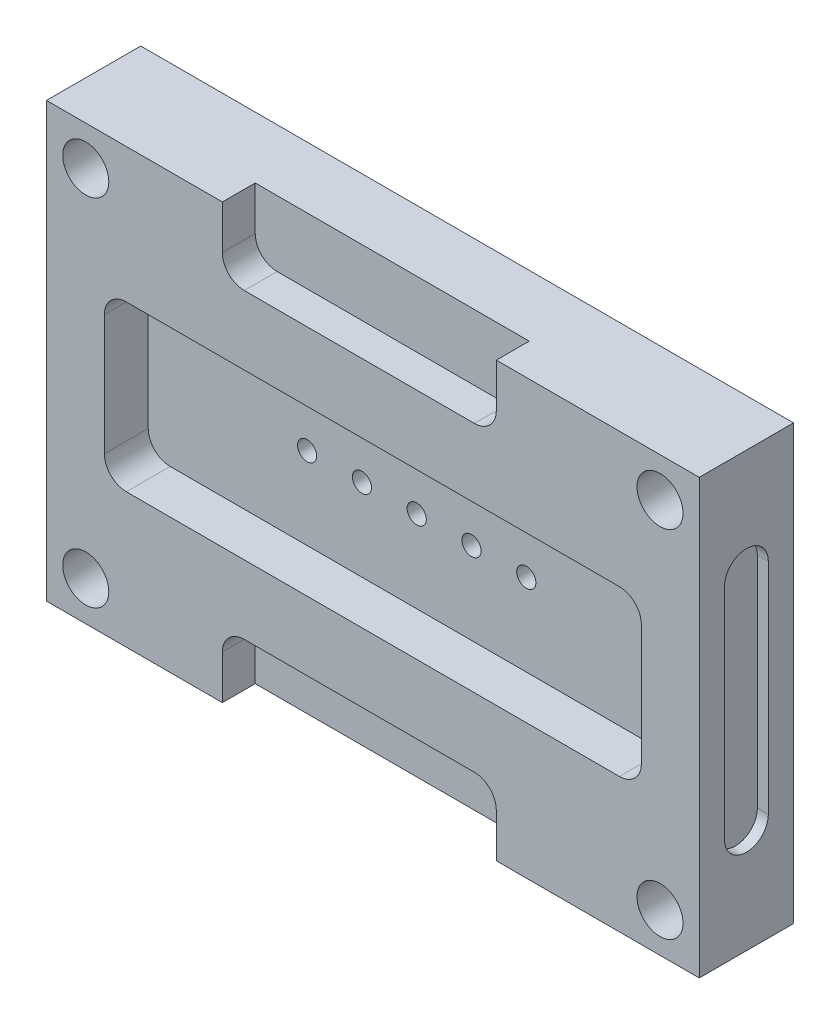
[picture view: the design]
ISO-10303-21;
HEADER;
FILE_DESCRIPTION(('STEP AP214'),'2;1');
FILE_NAME('part.step','',(''),(''),'','','');
FILE_SCHEMA(('AUTOMOTIVE_DESIGN { 1 0 10303 214 1 1 1 1 }'));
ENDSEC;
DATA;
#1=APPLICATION_CONTEXT('core data for automotive mechanical design processes');
#2=APPLICATION_PROTOCOL_DEFINITION('international standard','automotive_design',2000,#1);
#3=PRODUCT_CONTEXT('',#1,'mechanical');
#4=PRODUCT('Part','Part','',(#3));
#5=PRODUCT_RELATED_PRODUCT_CATEGORY('part','',(#4));
#6=PRODUCT_DEFINITION_FORMATION('','',#4);
#7=PRODUCT_DEFINITION_CONTEXT('part definition',#1,'design');
#8=PRODUCT_DEFINITION('design','',#6,#7);
#9=PRODUCT_DEFINITION_SHAPE('','',#8);
#10=(LENGTH_UNIT() NAMED_UNIT(*) SI_UNIT(.MILLI.,.METRE.));
#11=(NAMED_UNIT(*) PLANE_ANGLE_UNIT() SI_UNIT($,.RADIAN.));
#12=(NAMED_UNIT(*) SI_UNIT($,.STERADIAN.) SOLID_ANGLE_UNIT());
#13=UNCERTAINTY_MEASURE_WITH_UNIT(LENGTH_MEASURE(1.E-05),#10,'distance_accuracy_value','');
#14=(GEOMETRIC_REPRESENTATION_CONTEXT(3) GLOBAL_UNCERTAINTY_ASSIGNED_CONTEXT((#13)) GLOBAL_UNIT_ASSIGNED_CONTEXT((#10,
#11,#12)) REPRESENTATION_CONTEXT('',''));
#15=CARTESIAN_POINT('',(0.,0.,0.));
#16=DIRECTION('',(0.,0.,1.));
#17=DIRECTION('',(1.,0.,0.));
#18=AXIS2_PLACEMENT_3D('',#15,#16,#17);
#19=CARTESIAN_POINT('',(-297.85,197.85,86.));
#20=DIRECTION('',(1.,0.,0.));
#21=DIRECTION('',(0.,0.,-1.));
#22=AXIS2_PLACEMENT_3D('',#19,#20,#21);
#23=PLANE('',#22);
#24=DIRECTION('',(0.,-1.,0.));
#25=VECTOR('',#24,1.);
#26=CARTESIAN_POINT('',(-297.85,197.85,0.));
#27=LINE('',#26,#25);
#28=CARTESIAN_POINT('',(-297.85,197.85,0.));
#29=VERTEX_POINT('',#28);
#30=CARTESIAN_POINT('',(-297.85,-197.85,0.));
#31=VERTEX_POINT('',#30);
#32=EDGE_CURVE('E426',#29,#31,#27,.T.);
#33=ORIENTED_EDGE('',*,*,#32,.T.);
#34=DIRECTION('',(0.,0.,-1.));
#35=VECTOR('',#34,1.);
#36=CARTESIAN_POINT('',(-297.85,-197.85,86.));
#37=LINE('',#36,#35);
#38=CARTESIAN_POINT('',(-297.85,-197.85,86.));
#39=VERTEX_POINT('',#38);
#40=EDGE_CURVE('E12',#39,#31,#37,.T.);
#41=ORIENTED_EDGE('',*,*,#40,.F.);
#42=DIRECTION('',(0.,-1.,0.));
#43=VECTOR('',#42,1.);
#44=CARTESIAN_POINT('',(-297.85,197.85,86.));
#45=LINE('',#44,#43);
#46=CARTESIAN_POINT('',(-297.85,197.85,86.));
#47=VERTEX_POINT('',#46);
#48=EDGE_CURVE('E443',#47,#39,#45,.T.);
#49=ORIENTED_EDGE('',*,*,#48,.F.);
#50=DIRECTION('',(0.,0.,-1.));
#51=VECTOR('',#50,1.);
#52=CARTESIAN_POINT('',(-297.85,197.85,86.));
#53=LINE('',#52,#51);
#54=EDGE_CURVE('E292',#47,#29,#53,.T.);
#55=ORIENTED_EDGE('',*,*,#54,.T.);
#56=EDGE_LOOP('',(#33,#41,#49,#55));
#57=FACE_BOUND('',#56,.T.);
#58=ADVANCED_FACE('F41',(#57),#23,.F.);
#59=CARTESIAN_POINT('',(297.85,-197.85,86.));
#60=DIRECTION('',(0.,-1.,0.));
#61=DIRECTION('',(1.,0.,0.));
#62=AXIS2_PLACEMENT_3D('',#59,#60,#61);
#63=PLANE('',#62);
#64=DIRECTION('',(0.,0.,1.));
#65=VECTOR('',#64,1.);
#66=CARTESIAN_POINT('',(112.638390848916,-197.85,56.));
#67=LINE('',#66,#65);
#68=CARTESIAN_POINT('',(112.638390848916,-197.85,56.));
#69=VERTEX_POINT('',#68);
#70=CARTESIAN_POINT('',(112.638390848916,-197.85,86.));
#71=VERTEX_POINT('',#70);
#72=EDGE_CURVE('E776',#69,#71,#67,.T.);
#73=ORIENTED_EDGE('',*,*,#72,.F.);
#74=DIRECTION('',(1.,0.,0.));
#75=VECTOR('',#74,1.);
#76=CARTESIAN_POINT('',(-137.361609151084,-197.85,56.));
#77=LINE('',#76,#75);
#78=CARTESIAN_POINT('',(-137.361609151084,-197.85,56.));
#79=VERTEX_POINT('',#78);
#80=EDGE_CURVE('E542',#79,#69,#77,.T.);
#81=ORIENTED_EDGE('',*,*,#80,.F.);
#82=DIRECTION('',(0.,0.,1.));
#83=VECTOR('',#82,1.);
#84=CARTESIAN_POINT('',(-137.361609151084,-197.85,56.));
#85=LINE('',#84,#83);
#86=CARTESIAN_POINT('',(-137.361609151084,-197.85,86.));
#87=VERTEX_POINT('',#86);
#88=EDGE_CURVE('E765',#79,#87,#85,.T.);
#89=ORIENTED_EDGE('',*,*,#88,.T.);
#90=DIRECTION('',(-1.,0.,0.));
#91=VECTOR('',#90,1.);
#92=CARTESIAN_POINT('',(297.85,-197.85,86.));
#93=LINE('',#92,#91);
#94=EDGE_CURVE('E442',#87,#39,#93,.T.);
#95=ORIENTED_EDGE('',*,*,#94,.T.);
#96=ORIENTED_EDGE('',*,*,#40,.T.);
#97=DIRECTION('',(-1.,0.,0.));
#98=VECTOR('',#97,1.);
#99=CARTESIAN_POINT('',(297.85,-197.85,0.));
#100=LINE('',#99,#98);
#101=CARTESIAN_POINT('',(297.85,-197.85,0.));
#102=VERTEX_POINT('',#101);
#103=EDGE_CURVE('E283',#102,#31,#100,.T.);
#104=ORIENTED_EDGE('',*,*,#103,.F.);
#105=DIRECTION('',(0.,0.,-1.));
#106=VECTOR('',#105,1.);
#107=CARTESIAN_POINT('',(297.85,-197.85,86.));
#108=LINE('',#107,#106);
#109=CARTESIAN_POINT('',(297.85,-197.85,86.));
#110=VERTEX_POINT('',#109);
#111=EDGE_CURVE('E48',#110,#102,#108,.T.);
#112=ORIENTED_EDGE('',*,*,#111,.F.);
#113=EDGE_CURVE('E439',#110,#71,#93,.T.);
#114=ORIENTED_EDGE('',*,*,#113,.T.);
#115=EDGE_LOOP('',(#73,#81,#89,#95,#96,#104,#112,#114));
#116=FACE_BOUND('',#115,.T.);
#117=ADVANCED_FACE('F742',(#116),#63,.T.);
#118=CARTESIAN_POINT('',(297.85,-197.85,86.));
#119=DIRECTION('',(-1.,0.,0.));
#120=DIRECTION('',(0.,-1.,0.));
#121=AXIS2_PLACEMENT_3D('',#118,#119,#120);
#122=PLANE('',#121);
#123=DIRECTION('',(0.,1.,0.));
#124=VECTOR('',#123,1.);
#125=CARTESIAN_POINT('',(297.85,-100.,23.));
#126=LINE('',#125,#124);
#127=CARTESIAN_POINT('',(297.85,-100.,23.));
#128=VERTEX_POINT('',#127);
#129=CARTESIAN_POINT('',(297.85,100.,23.));
#130=VERTEX_POINT('',#129);
#131=EDGE_CURVE('E552',#128,#130,#126,.T.);
#132=ORIENTED_EDGE('',*,*,#131,.F.);
#133=CARTESIAN_POINT('',(297.85,-100.,43.));
#134=DIRECTION('',(1.,0.,0.));
#135=DIRECTION('',(0.,1.,0.));
#136=AXIS2_PLACEMENT_3D('',#133,#134,#135);
#137=CIRCLE('',#136,20.);
#138=CARTESIAN_POINT('',(297.85,-100.,63.));
#139=VERTEX_POINT('',#138);
#140=EDGE_CURVE('E55',#139,#128,#137,.T.);
#141=ORIENTED_EDGE('',*,*,#140,.F.);
#142=DIRECTION('',(0.,-1.,0.));
#143=VECTOR('',#142,1.);
#144=CARTESIAN_POINT('',(297.85,-100.,63.));
#145=LINE('',#144,#143);
#146=CARTESIAN_POINT('',(297.85,100.,63.));
#147=VERTEX_POINT('',#146);
#148=EDGE_CURVE('E244',#147,#139,#145,.T.);
#149=ORIENTED_EDGE('',*,*,#148,.F.);
#150=CARTESIAN_POINT('',(297.85,100.,43.));
#151=DIRECTION('',(1.,0.,0.));
#152=DIRECTION('',(0.,1.,0.));
#153=AXIS2_PLACEMENT_3D('',#150,#151,#152);
#154=CIRCLE('',#153,20.);
#155=EDGE_CURVE('E247',#130,#147,#154,.T.);
#156=ORIENTED_EDGE('',*,*,#155,.F.);
#157=EDGE_LOOP('',(#132,#141,#149,#156));
#158=FACE_BOUND('',#157,.T.);
#159=DIRECTION('',(0.,1.,0.));
#160=VECTOR('',#159,1.);
#161=CARTESIAN_POINT('',(297.85,-197.85,0.));
#162=LINE('',#161,#160);
#163=CARTESIAN_POINT('',(297.85,197.85,0.));
#164=VERTEX_POINT('',#163);
#165=EDGE_CURVE('E277',#102,#164,#162,.T.);
#166=ORIENTED_EDGE('',*,*,#165,.T.);
#167=DIRECTION('',(0.,0.,-1.));
#168=VECTOR('',#167,1.);
#169=CARTESIAN_POINT('',(297.85,197.85,86.));
#170=LINE('',#169,#168);
#171=CARTESIAN_POINT('',(297.85,197.85,86.));
#172=VERTEX_POINT('',#171);
#173=EDGE_CURVE('E290',#172,#164,#170,.T.);
#174=ORIENTED_EDGE('',*,*,#173,.F.);
#175=DIRECTION('',(0.,1.,0.));
#176=VECTOR('',#175,1.);
#177=CARTESIAN_POINT('',(297.85,-197.85,86.));
#178=LINE('',#177,#176);
#179=EDGE_CURVE('E423',#110,#172,#178,.T.);
#180=ORIENTED_EDGE('',*,*,#179,.F.);
#181=ORIENTED_EDGE('',*,*,#111,.T.);
#182=EDGE_LOOP('',(#166,#174,#180,#181));
#183=FACE_BOUND('',#182,.T.);
#184=ADVANCED_FACE('F568',(#158,#183),#122,.F.);
#185=CARTESIAN_POINT('',(-297.85,197.85,86.));
#186=DIRECTION('',(0.,1.,0.));
#187=DIRECTION('',(0.,0.,1.));
#188=AXIS2_PLACEMENT_3D('',#185,#186,#187);
#189=PLANE('',#188);
#190=DIRECTION('',(0.,0.,1.));
#191=VECTOR('',#190,1.);
#192=CARTESIAN_POINT('',(-137.361609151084,197.85,56.));
#193=LINE('',#192,#191);
#194=CARTESIAN_POINT('',(-137.361609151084,197.85,56.));
#195=VERTEX_POINT('',#194);
#196=CARTESIAN_POINT('',(-137.361609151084,197.85,86.));
#197=VERTEX_POINT('',#196);
#198=EDGE_CURVE('E349',#195,#197,#193,.T.);
#199=ORIENTED_EDGE('',*,*,#198,.F.);
#200=DIRECTION('',(-1.,0.,0.));
#201=VECTOR('',#200,1.);
#202=CARTESIAN_POINT('',(-137.361609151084,197.85,56.));
#203=LINE('',#202,#201);
#204=CARTESIAN_POINT('',(112.638390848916,197.85,56.));
#205=VERTEX_POINT('',#204);
#206=EDGE_CURVE('E341',#205,#195,#203,.T.);
#207=ORIENTED_EDGE('',*,*,#206,.F.);
#208=DIRECTION('',(0.,0.,1.));
#209=VECTOR('',#208,1.);
#210=CARTESIAN_POINT('',(112.638390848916,197.85,56.));
#211=LINE('',#210,#209);
#212=CARTESIAN_POINT('',(112.638390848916,197.85,86.));
#213=VERTEX_POINT('',#212);
#214=EDGE_CURVE('E353',#205,#213,#211,.T.);
#215=ORIENTED_EDGE('',*,*,#214,.T.);
#216=DIRECTION('',(1.,0.,0.));
#217=VECTOR('',#216,1.);
#218=CARTESIAN_POINT('',(-297.85,197.85,86.));
#219=LINE('',#218,#217);
#220=EDGE_CURVE('E422',#213,#172,#219,.T.);
#221=ORIENTED_EDGE('',*,*,#220,.T.);
#222=ORIENTED_EDGE('',*,*,#173,.T.);
#223=DIRECTION('',(1.,0.,0.));
#224=VECTOR('',#223,1.);
#225=CARTESIAN_POINT('',(-297.85,197.85,0.));
#226=LINE('',#225,#224);
#227=EDGE_CURVE('E282',#29,#164,#226,.T.);
#228=ORIENTED_EDGE('',*,*,#227,.F.);
#229=ORIENTED_EDGE('',*,*,#54,.F.);
#230=EDGE_CURVE('E418',#47,#197,#219,.T.);
#231=ORIENTED_EDGE('',*,*,#230,.T.);
#232=EDGE_LOOP('',(#199,#207,#215,#221,#222,#228,#229,#231));
#233=FACE_BOUND('',#232,.T.);
#234=ADVANCED_FACE('F770',(#233),#189,.T.);
#235=CARTESIAN_POINT('',(-297.85,197.85,86.));
#236=DIRECTION('',(0.,0.,1.));
#237=DIRECTION('',(1.,0.,0.));
#238=AXIS2_PLACEMENT_3D('',#235,#236,#237);
#239=PLANE('',#238);
#240=DIRECTION('',(0.,1.,0.));
#241=VECTOR('',#240,1.);
#242=CARTESIAN_POINT('',(112.638390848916,-197.85,86.));
#243=LINE('',#242,#241);
#244=CARTESIAN_POINT('',(112.638390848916,-157.85,86.));
#245=VERTEX_POINT('',#244);
#246=EDGE_CURVE('E459',#71,#245,#243,.T.);
#247=ORIENTED_EDGE('',*,*,#246,.F.);
#248=ORIENTED_EDGE('',*,*,#113,.F.);
#249=ORIENTED_EDGE('',*,*,#179,.T.);
#250=ORIENTED_EDGE('',*,*,#220,.F.);
#251=DIRECTION('',(0.,1.,0.));
#252=VECTOR('',#251,1.);
#253=CARTESIAN_POINT('',(112.638390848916,197.85,86.));
#254=LINE('',#253,#252);
#255=CARTESIAN_POINT('',(112.638390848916,157.85,86.));
#256=VERTEX_POINT('',#255);
#257=EDGE_CURVE('E354',#256,#213,#254,.T.);
#258=ORIENTED_EDGE('',*,*,#257,.F.);
#259=CARTESIAN_POINT('',(92.6383908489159,157.85,86.));
#260=DIRECTION('',(0.,0.,1.));
#261=DIRECTION('',(-1.,0.,0.));
#262=AXIS2_PLACEMENT_3D('',#259,#260,#261);
#263=CIRCLE('',#262,20.);
#264=CARTESIAN_POINT('',(92.6383908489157,137.85,86.));
#265=VERTEX_POINT('',#264);
#266=EDGE_CURVE('E389',#265,#256,#263,.T.);
#267=ORIENTED_EDGE('',*,*,#266,.F.);
#268=DIRECTION('',(1.,0.,0.));
#269=VECTOR('',#268,1.);
#270=CARTESIAN_POINT('',(92.6383908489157,137.85,86.));
#271=LINE('',#270,#269);
#272=CARTESIAN_POINT('',(-117.361609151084,137.85,86.));
#273=VERTEX_POINT('',#272);
#274=EDGE_CURVE('E371',#273,#265,#271,.T.);
#275=ORIENTED_EDGE('',*,*,#274,.F.);
#276=CARTESIAN_POINT('',(-117.361609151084,157.85,86.));
#277=DIRECTION('',(0.,0.,1.));
#278=DIRECTION('',(-1.,0.,0.));
#279=AXIS2_PLACEMENT_3D('',#276,#277,#278);
#280=CIRCLE('',#279,20.);
#281=CARTESIAN_POINT('',(-137.361609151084,157.85,86.));
#282=VERTEX_POINT('',#281);
#283=EDGE_CURVE('E379',#282,#273,#280,.T.);
#284=ORIENTED_EDGE('',*,*,#283,.F.);
#285=DIRECTION('',(0.,-1.,0.));
#286=VECTOR('',#285,1.);
#287=CARTESIAN_POINT('',(-137.361609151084,197.85,86.));
#288=LINE('',#287,#286);
#289=EDGE_CURVE('E383',#197,#282,#288,.T.);
#290=ORIENTED_EDGE('',*,*,#289,.F.);
#291=ORIENTED_EDGE('',*,*,#230,.F.);
#292=ORIENTED_EDGE('',*,*,#48,.T.);
#293=ORIENTED_EDGE('',*,*,#94,.F.);
#294=DIRECTION('',(0.,-1.,0.));
#295=VECTOR('',#294,1.);
#296=CARTESIAN_POINT('',(-137.361609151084,-197.85,86.));
#297=LINE('',#296,#295);
#298=CARTESIAN_POINT('',(-137.361609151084,-157.85,86.));
#299=VERTEX_POINT('',#298);
#300=EDGE_CURVE('E457',#299,#87,#297,.T.);
#301=ORIENTED_EDGE('',*,*,#300,.F.);
#302=CARTESIAN_POINT('',(-117.361609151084,-157.85,86.));
#303=DIRECTION('',(0.,0.,1.));
#304=DIRECTION('',(1.,0.,0.));
#305=AXIS2_PLACEMENT_3D('',#302,#303,#304);
#306=CIRCLE('',#305,20.);
#307=CARTESIAN_POINT('',(-117.361609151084,-137.85,86.));
#308=VERTEX_POINT('',#307);
#309=EDGE_CURVE('E460',#308,#299,#306,.T.);
#310=ORIENTED_EDGE('',*,*,#309,.F.);
#311=DIRECTION('',(-1.,0.,0.));
#312=VECTOR('',#311,1.);
#313=CARTESIAN_POINT('',(92.6383908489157,-137.85,86.));
#314=LINE('',#313,#312);
#315=CARTESIAN_POINT('',(92.6383908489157,-137.85,86.));
#316=VERTEX_POINT('',#315);
#317=EDGE_CURVE('E472',#316,#308,#314,.T.);
#318=ORIENTED_EDGE('',*,*,#317,.F.);
#319=CARTESIAN_POINT('',(92.6383908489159,-157.85,86.));
#320=DIRECTION('',(0.,0.,1.));
#321=DIRECTION('',(1.,0.,0.));
#322=AXIS2_PLACEMENT_3D('',#319,#320,#321);
#323=CIRCLE('',#322,20.);
#324=EDGE_CURVE('E63',#245,#316,#323,.T.);
#325=ORIENTED_EDGE('',*,*,#324,.F.);
#326=EDGE_LOOP('',(#247,#248,#249,#250,#258,#267,#275,#284,#290,#291,#292,#293,#301,#310,#318,#325));
#327=FACE_BOUND('',#326,.T.);
#328=CARTESIAN_POINT('',(-225.,55.,86.));
#329=DIRECTION('',(0.,0.,1.));
#330=DIRECTION('',(-1.,0.,0.));
#331=AXIS2_PLACEMENT_3D('',#328,#329,#330);
#332=CIRCLE('',#331,20.);
#333=CARTESIAN_POINT('',(-225.,75.,86.));
#334=VERTEX_POINT('',#333);
#335=CARTESIAN_POINT('',(-245.,55.,86.));
#336=VERTEX_POINT('',#335);
#337=EDGE_CURVE('E307',#334,#336,#332,.T.);
#338=ORIENTED_EDGE('',*,*,#337,.F.);
#339=DIRECTION('',(-1.,0.,0.));
#340=VECTOR('',#339,1.);
#341=CARTESIAN_POINT('',(-225.,75.,86.));
#342=LINE('',#341,#340);
#343=CARTESIAN_POINT('',(225.,75.,86.));
#344=VERTEX_POINT('',#343);
#345=EDGE_CURVE('E689',#344,#334,#342,.T.);
#346=ORIENTED_EDGE('',*,*,#345,.F.);
#347=CARTESIAN_POINT('',(225.,55.,86.));
#348=DIRECTION('',(0.,0.,1.));
#349=DIRECTION('',(-1.,0.,0.));
#350=AXIS2_PLACEMENT_3D('',#347,#348,#349);
#351=CIRCLE('',#350,20.);
#352=CARTESIAN_POINT('',(245.,55.,86.));
#353=VERTEX_POINT('',#352);
#354=EDGE_CURVE('E695',#353,#344,#351,.T.);
#355=ORIENTED_EDGE('',*,*,#354,.F.);
#356=DIRECTION('',(0.,1.,0.));
#357=VECTOR('',#356,1.);
#358=CARTESIAN_POINT('',(245.,-55.,86.));
#359=LINE('',#358,#357);
#360=CARTESIAN_POINT('',(245.,-55.,86.));
#361=VERTEX_POINT('',#360);
#362=EDGE_CURVE('E697',#361,#353,#359,.T.);
#363=ORIENTED_EDGE('',*,*,#362,.F.);
#364=CARTESIAN_POINT('',(225.,-55.,86.));
#365=DIRECTION('',(0.,0.,1.));
#366=DIRECTION('',(1.,0.,0.));
#367=AXIS2_PLACEMENT_3D('',#364,#365,#366);
#368=CIRCLE('',#367,20.);
#369=CARTESIAN_POINT('',(225.,-75.,86.));
#370=VERTEX_POINT('',#369);
#371=EDGE_CURVE('E725',#370,#361,#368,.T.);
#372=ORIENTED_EDGE('',*,*,#371,.F.);
#373=DIRECTION('',(1.,0.,0.));
#374=VECTOR('',#373,1.);
#375=CARTESIAN_POINT('',(-225.,-75.,86.));
#376=LINE('',#375,#374);
#377=CARTESIAN_POINT('',(-225.,-75.,86.));
#378=VERTEX_POINT('',#377);
#379=EDGE_CURVE('E715',#378,#370,#376,.T.);
#380=ORIENTED_EDGE('',*,*,#379,.F.);
#381=CARTESIAN_POINT('',(-225.,-55.,86.));
#382=DIRECTION('',(0.,0.,1.));
#383=DIRECTION('',(-1.,0.,0.));
#384=AXIS2_PLACEMENT_3D('',#381,#382,#383);
#385=CIRCLE('',#384,20.);
#386=CARTESIAN_POINT('',(-245.,-55.,86.));
#387=VERTEX_POINT('',#386);
#388=EDGE_CURVE('E306',#387,#378,#385,.T.);
#389=ORIENTED_EDGE('',*,*,#388,.F.);
#390=DIRECTION('',(0.,-1.,0.));
#391=VECTOR('',#390,1.);
#392=CARTESIAN_POINT('',(-245.,-55.,86.));
#393=LINE('',#392,#391);
#394=EDGE_CURVE('E301',#336,#387,#393,.T.);
#395=ORIENTED_EDGE('',*,*,#394,.F.);
#396=EDGE_LOOP('',(#338,#346,#355,#363,#372,#380,#389,#395));
#397=FACE_BOUND('',#396,.T.);
#398=CARTESIAN_POINT('',(262.,162.,85.99999999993));
#399=DIRECTION('',(0.,0.,1.));
#400=DIRECTION('',(1.,0.,0.));
#401=AXIS2_PLACEMENT_3D('',#398,#399,#400);
#402=CIRCLE('',#401,21.);
#403=CARTESIAN_POINT('',(283.,162.,85.99999999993));
#404=VERTEX_POINT('',#403);
#405=EDGE_CURVE('E615',#404,#404,#402,.T.);
#406=ORIENTED_EDGE('',*,*,#405,.F.);
#407=EDGE_LOOP('',(#406));
#408=FACE_BOUND('',#407,.T.);
#409=CARTESIAN_POINT('',(-262.,162.,85.9999999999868));
#410=DIRECTION('',(0.,0.,1.));
#411=DIRECTION('',(1.,0.,0.));
#412=AXIS2_PLACEMENT_3D('',#409,#410,#411);
#413=CIRCLE('',#412,21.);
#414=CARTESIAN_POINT('',(-241.,162.,85.9999999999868));
#415=VERTEX_POINT('',#414);
#416=EDGE_CURVE('E602',#415,#415,#413,.T.);
#417=ORIENTED_EDGE('',*,*,#416,.F.);
#418=EDGE_LOOP('',(#417));
#419=FACE_BOUND('',#418,.T.);
#420=CARTESIAN_POINT('',(-262.,-162.,85.9999999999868));
#421=DIRECTION('',(0.,0.,1.));
#422=DIRECTION('',(1.,0.,0.));
#423=AXIS2_PLACEMENT_3D('',#420,#421,#422);
#424=CIRCLE('',#423,21.);
#425=CARTESIAN_POINT('',(-241.,-162.,85.9999999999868));
#426=VERTEX_POINT('',#425);
#427=EDGE_CURVE('E601',#426,#426,#424,.T.);
#428=ORIENTED_EDGE('',*,*,#427,.F.);
#429=EDGE_LOOP('',(#428));
#430=FACE_BOUND('',#429,.T.);
#431=CARTESIAN_POINT('',(262.,-162.,86.));
#432=DIRECTION('',(0.,0.,1.));
#433=DIRECTION('',(1.,0.,0.));
#434=AXIS2_PLACEMENT_3D('',#431,#432,#433);
#435=CIRCLE('',#434,21.);
#436=CARTESIAN_POINT('',(283.,-162.,86.));
#437=VERTEX_POINT('',#436);
#438=EDGE_CURVE('E600',#437,#437,#435,.T.);
#439=ORIENTED_EDGE('',*,*,#438,.F.);
#440=EDGE_LOOP('',(#439));
#441=FACE_BOUND('',#440,.T.);
#442=ADVANCED_FACE('F386',(#327,#397,#408,#419,#430,#441),#239,.T.);
#443=CARTESIAN_POINT('',(-297.85,197.85,0.));
#444=DIRECTION('',(0.,0.,1.));
#445=DIRECTION('',(1.,0.,0.));
#446=AXIS2_PLACEMENT_3D('',#443,#444,#445);
#447=PLANE('',#446);
#448=CARTESIAN_POINT('',(0.,0.,0.));
#449=DIRECTION('',(0.,0.,1.));
#450=DIRECTION('',(1.,0.,0.));
#451=AXIS2_PLACEMENT_3D('',#448,#449,#450);
#452=CIRCLE('',#451,8.74999999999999);
#453=CARTESIAN_POINT('',(8.74999999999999,0.,0.));
#454=VERTEX_POINT('',#453);
#455=EDGE_CURVE('E817',#454,#454,#452,.T.);
#456=ORIENTED_EDGE('',*,*,#455,.T.);
#457=EDGE_LOOP('',(#456));
#458=FACE_BOUND('',#457,.T.);
#459=CARTESIAN_POINT('',(-50.,0.,0.));
#460=DIRECTION('',(0.,0.,1.));
#461=DIRECTION('',(1.,0.,0.));
#462=AXIS2_PLACEMENT_3D('',#459,#460,#461);
#463=CIRCLE('',#462,8.74999999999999);
#464=CARTESIAN_POINT('',(-41.25,0.,0.));
#465=VERTEX_POINT('',#464);
#466=EDGE_CURVE('E805',#465,#465,#463,.T.);
#467=ORIENTED_EDGE('',*,*,#466,.T.);
#468=EDGE_LOOP('',(#467));
#469=FACE_BOUND('',#468,.T.);
#470=CARTESIAN_POINT('',(-100.,0.,0.));
#471=DIRECTION('',(0.,0.,1.));
#472=DIRECTION('',(1.,0.,0.));
#473=AXIS2_PLACEMENT_3D('',#470,#471,#472);
#474=CIRCLE('',#473,8.74999999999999);
#475=CARTESIAN_POINT('',(-91.25,0.,0.));
#476=VERTEX_POINT('',#475);
#477=EDGE_CURVE('E791',#476,#476,#474,.T.);
#478=ORIENTED_EDGE('',*,*,#477,.T.);
#479=EDGE_LOOP('',(#478));
#480=FACE_BOUND('',#479,.T.);
#481=CARTESIAN_POINT('',(50.,0.,0.));
#482=DIRECTION('',(0.,0.,1.));
#483=DIRECTION('',(1.,0.,0.));
#484=AXIS2_PLACEMENT_3D('',#481,#482,#483);
#485=CIRCLE('',#484,8.74999999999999);
#486=CARTESIAN_POINT('',(58.75,0.,0.));
#487=VERTEX_POINT('',#486);
#488=EDGE_CURVE('E575',#487,#487,#485,.T.);
#489=ORIENTED_EDGE('',*,*,#488,.T.);
#490=EDGE_LOOP('',(#489));
#491=FACE_BOUND('',#490,.T.);
#492=CARTESIAN_POINT('',(100.,0.,0.));
#493=DIRECTION('',(0.,0.,1.));
#494=DIRECTION('',(1.,0.,0.));
#495=AXIS2_PLACEMENT_3D('',#492,#493,#494);
#496=CIRCLE('',#495,8.74999999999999);
#497=CARTESIAN_POINT('',(108.75,0.,0.));
#498=VERTEX_POINT('',#497);
#499=EDGE_CURVE('E251',#498,#498,#496,.T.);
#500=ORIENTED_EDGE('',*,*,#499,.T.);
#501=EDGE_LOOP('',(#500));
#502=FACE_BOUND('',#501,.T.);
#503=CARTESIAN_POINT('',(262.,162.,0.));
#504=DIRECTION('',(0.,0.,1.));
#505=DIRECTION('',(1.,0.,0.));
#506=AXIS2_PLACEMENT_3D('',#503,#504,#505);
#507=CIRCLE('',#506,21.);
#508=CARTESIAN_POINT('',(283.,162.,0.));
#509=VERTEX_POINT('',#508);
#510=EDGE_CURVE('E326',#509,#509,#507,.T.);
#511=ORIENTED_EDGE('',*,*,#510,.T.);
#512=EDGE_LOOP('',(#511));
#513=FACE_BOUND('',#512,.T.);
#514=CARTESIAN_POINT('',(-262.,162.,0.));
#515=DIRECTION('',(0.,0.,1.));
#516=DIRECTION('',(1.,0.,0.));
#517=AXIS2_PLACEMENT_3D('',#514,#515,#516);
#518=CIRCLE('',#517,21.);
#519=CARTESIAN_POINT('',(-241.,162.,0.));
#520=VERTEX_POINT('',#519);
#521=EDGE_CURVE('E612',#520,#520,#518,.T.);
#522=ORIENTED_EDGE('',*,*,#521,.T.);
#523=EDGE_LOOP('',(#522));
#524=FACE_BOUND('',#523,.T.);
#525=CARTESIAN_POINT('',(-262.,-162.,0.));
#526=DIRECTION('',(0.,0.,1.));
#527=DIRECTION('',(1.,0.,0.));
#528=AXIS2_PLACEMENT_3D('',#525,#526,#527);
#529=CIRCLE('',#528,21.);
#530=CARTESIAN_POINT('',(-241.,-162.,0.));
#531=VERTEX_POINT('',#530);
#532=EDGE_CURVE('E596',#531,#531,#529,.T.);
#533=ORIENTED_EDGE('',*,*,#532,.T.);
#534=EDGE_LOOP('',(#533));
#535=FACE_BOUND('',#534,.T.);
#536=CARTESIAN_POINT('',(262.,-162.,0.));
#537=DIRECTION('',(0.,0.,1.));
#538=DIRECTION('',(1.,0.,0.));
#539=AXIS2_PLACEMENT_3D('',#536,#537,#538);
#540=CIRCLE('',#539,21.);
#541=CARTESIAN_POINT('',(283.,-162.,0.));
#542=VERTEX_POINT('',#541);
#543=EDGE_CURVE('E622',#542,#542,#540,.T.);
#544=ORIENTED_EDGE('',*,*,#543,.T.);
#545=EDGE_LOOP('',(#544));
#546=FACE_BOUND('',#545,.T.);
#547=ORIENTED_EDGE('',*,*,#32,.F.);
#548=ORIENTED_EDGE('',*,*,#227,.T.);
#549=ORIENTED_EDGE('',*,*,#165,.F.);
#550=ORIENTED_EDGE('',*,*,#103,.T.);
#551=EDGE_LOOP('',(#547,#548,#549,#550));
#552=FACE_BOUND('',#551,.T.);
#553=ADVANCED_FACE('F758',(#458,#469,#480,#491,#502,#513,#524,#535,#546,#552),#447,.F.);
#554=CARTESIAN_POINT('',(262.,-162.,0.));
#555=DIRECTION('',(0.,0.,1.));
#556=DIRECTION('',(1.,0.,0.));
#557=AXIS2_PLACEMENT_3D('',#554,#555,#556);
#558=CYLINDRICAL_SURFACE('',#557,21.);
#559=ORIENTED_EDGE('',*,*,#543,.F.);
#560=EDGE_LOOP('',(#559));
#561=FACE_BOUND('',#560,.T.);
#562=ORIENTED_EDGE('',*,*,#438,.T.);
#563=EDGE_LOOP('',(#562));
#564=FACE_BOUND('',#563,.T.);
#565=ADVANCED_FACE('F1172',(#561,#564),#558,.F.);
#566=CARTESIAN_POINT('',(-262.,-162.,0.));
#567=DIRECTION('',(0.,0.,1.));
#568=DIRECTION('',(1.,0.,0.));
#569=AXIS2_PLACEMENT_3D('',#566,#567,#568);
#570=CYLINDRICAL_SURFACE('',#569,21.);
#571=CARTESIAN_POINT('',(-241.,-162.,0.));
#572=CARTESIAN_POINT('',(-241.,-162.,0.895833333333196));
#573=CARTESIAN_POINT('',(-241.,-162.,1.79166666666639));
#574=CARTESIAN_POINT('',(-241.,-162.,3.58333333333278));
#575=CARTESIAN_POINT('',(-241.,-162.,4.47916666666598));
#576=CARTESIAN_POINT('',(-241.,-162.,6.27083333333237));
#577=CARTESIAN_POINT('',(-241.,-162.,7.16666666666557));
#578=CARTESIAN_POINT('',(-241.,-162.,8.95833333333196));
#579=CARTESIAN_POINT('',(-241.,-162.,9.85416666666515));
#580=CARTESIAN_POINT('',(-241.,-162.,11.6458333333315));
#581=CARTESIAN_POINT('',(-241.,-162.,12.5416666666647));
#582=CARTESIAN_POINT('',(-241.,-162.,14.3333333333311));
#583=CARTESIAN_POINT('',(-241.,-162.,15.2291666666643));
#584=CARTESIAN_POINT('',(-241.,-162.,17.0208333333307));
#585=CARTESIAN_POINT('',(-241.,-162.,17.9166666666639));
#586=CARTESIAN_POINT('',(-241.,-162.,19.7083333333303));
#587=CARTESIAN_POINT('',(-241.,-162.,20.6041666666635));
#588=CARTESIAN_POINT('',(-241.,-162.,22.3958333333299));
#589=CARTESIAN_POINT('',(-241.,-162.,23.2916666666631));
#590=CARTESIAN_POINT('',(-241.,-162.,25.0833333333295));
#591=CARTESIAN_POINT('',(-241.,-162.,25.9791666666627));
#592=CARTESIAN_POINT('',(-241.,-162.,27.7708333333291));
#593=CARTESIAN_POINT('',(-241.,-162.,28.6666666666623));
#594=CARTESIAN_POINT('',(-241.,-162.,30.4583333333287));
#595=CARTESIAN_POINT('',(-241.,-162.,31.3541666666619));
#596=CARTESIAN_POINT('',(-241.,-162.,33.1458333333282));
#597=CARTESIAN_POINT('',(-241.,-162.,34.0416666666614));
#598=CARTESIAN_POINT('',(-241.,-162.,35.8333333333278));
#599=CARTESIAN_POINT('',(-241.,-162.,36.729166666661));
#600=CARTESIAN_POINT('',(-241.,-162.,38.5208333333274));
#601=CARTESIAN_POINT('',(-241.,-162.,39.4166666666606));
#602=CARTESIAN_POINT('',(-241.,-162.,41.208333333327));
#603=CARTESIAN_POINT('',(-241.,-162.,42.1041666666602));
#604=CARTESIAN_POINT('',(-241.,-162.,43.8958333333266));
#605=CARTESIAN_POINT('',(-241.,-162.,44.7916666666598));
#606=CARTESIAN_POINT('',(-241.,-162.,46.5833333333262));
#607=CARTESIAN_POINT('',(-241.,-162.,47.4791666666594));
#608=CARTESIAN_POINT('',(-241.,-162.,49.2708333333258));
#609=CARTESIAN_POINT('',(-241.,-162.,50.166666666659));
#610=CARTESIAN_POINT('',(-241.,-162.,51.9583333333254));
#611=CARTESIAN_POINT('',(-241.,-162.,52.8541666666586));
#612=CARTESIAN_POINT('',(-241.,-162.,54.6458333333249));
#613=CARTESIAN_POINT('',(-241.,-162.,55.5416666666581));
#614=CARTESIAN_POINT('',(-241.,-162.,57.3333333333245));
#615=CARTESIAN_POINT('',(-241.,-162.,58.2291666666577));
#616=CARTESIAN_POINT('',(-241.,-162.,60.0208333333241));
#617=CARTESIAN_POINT('',(-241.,-162.,60.9166666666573));
#618=CARTESIAN_POINT('',(-241.,-162.,62.7083333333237));
#619=CARTESIAN_POINT('',(-241.,-162.,63.6041666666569));
#620=CARTESIAN_POINT('',(-241.,-162.,65.3958333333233));
#621=CARTESIAN_POINT('',(-241.,-162.,66.2916666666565));
#622=CARTESIAN_POINT('',(-241.,-162.,68.0833333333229));
#623=CARTESIAN_POINT('',(-241.,-162.,68.9791666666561));
#624=CARTESIAN_POINT('',(-241.,-162.,70.7708333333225));
#625=CARTESIAN_POINT('',(-241.,-162.,71.6666666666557));
#626=CARTESIAN_POINT('',(-241.,-162.,73.458333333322));
#627=CARTESIAN_POINT('',(-241.,-162.,74.3541666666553));
#628=CARTESIAN_POINT('',(-241.,-162.,76.1458333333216));
#629=CARTESIAN_POINT('',(-241.,-162.,77.0416666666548));
#630=CARTESIAN_POINT('',(-241.,-162.,78.8333333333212));
#631=CARTESIAN_POINT('',(-241.,-162.,79.7291666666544));
#632=CARTESIAN_POINT('',(-241.,-162.,81.5208333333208));
#633=CARTESIAN_POINT('',(-241.,-162.,82.416666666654));
#634=CARTESIAN_POINT('',(-241.,-162.,84.2083333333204));
#635=CARTESIAN_POINT('',(-241.,-162.,85.1041666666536));
#636=CARTESIAN_POINT('',(-241.,-162.,85.9999999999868));
#637=B_SPLINE_CURVE_WITH_KNOTS('',3,(#571,#572,#573,#574,#575,#576,#577,#578,#579,#580,#581,
#582,#583,#584,#585,#586,#587,#588,#589,#590,#591,#592,#593,#594,#595,#596,#597,#598,#599,#600,
#601,#602,#603,#604,#605,#606,#607,#608,#609,#610,#611,#612,#613,#614,#615,#616,#617,#618,#619,
#620,#621,#622,#623,#624,#625,#626,#627,#628,#629,#630,#631,#632,#633,#634,#635,#636),
.UNSPECIFIED.,.F.,.F.,(4,2,2,2,2,2,2,2,2,2,2,2,2,2,2,2,2,2,2,2,2,2,2,2,2,2,2,2,2,2,2,2,4),(0.,
2.68749999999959,5.37499999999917,8.06249999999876,10.7499999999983,13.4374999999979,
16.1249999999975,18.8124999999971,21.4999999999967,24.1874999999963,26.8749999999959,
29.5624999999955,32.249999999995,34.9374999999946,37.6249999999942,40.3124999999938,
42.9999999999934,45.687499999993,48.3749999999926,51.0624999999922,53.7499999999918,
56.4374999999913,59.1249999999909,61.8124999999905,64.4999999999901,67.1874999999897,
69.8749999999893,72.5624999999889,75.2499999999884,77.937499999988,80.6249999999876,
83.3124999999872,85.9999999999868),.UNSPECIFIED.);
#638=EDGE_CURVE('BSEAM1162',#531,#426,#637,.T.);
#639=ORIENTED_EDGE('',*,*,#532,.F.);
#640=ORIENTED_EDGE('',*,*,#427,.T.);
#641=ORIENTED_EDGE('',*,*,#638,.T.);
#642=ORIENTED_EDGE('',*,*,#638,.F.);
#643=EDGE_LOOP('',(#639,#641,#640,#642));
#644=FACE_BOUND('',#643,.T.);
#645=ADVANCED_FACE('F1162',(#644),#570,.F.);
#646=CARTESIAN_POINT('',(-262.,162.,0.));
#647=DIRECTION('',(0.,0.,1.));
#648=DIRECTION('',(1.,0.,0.));
#649=AXIS2_PLACEMENT_3D('',#646,#647,#648);
#650=CYLINDRICAL_SURFACE('',#649,21.);
#651=CARTESIAN_POINT('',(-241.,162.,0.));
#652=CARTESIAN_POINT('',(-241.,162.,0.895833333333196));
#653=CARTESIAN_POINT('',(-241.,162.,1.79166666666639));
#654=CARTESIAN_POINT('',(-241.,162.,3.58333333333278));
#655=CARTESIAN_POINT('',(-241.,162.,4.47916666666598));
#656=CARTESIAN_POINT('',(-241.,162.,6.27083333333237));
#657=CARTESIAN_POINT('',(-241.,162.,7.16666666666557));
#658=CARTESIAN_POINT('',(-241.,162.,8.95833333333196));
#659=CARTESIAN_POINT('',(-241.,162.,9.85416666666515));
#660=CARTESIAN_POINT('',(-241.,162.,11.6458333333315));
#661=CARTESIAN_POINT('',(-241.,162.,12.5416666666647));
#662=CARTESIAN_POINT('',(-241.,162.,14.3333333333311));
#663=CARTESIAN_POINT('',(-241.,162.,15.2291666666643));
#664=CARTESIAN_POINT('',(-241.,162.,17.0208333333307));
#665=CARTESIAN_POINT('',(-241.,162.,17.9166666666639));
#666=CARTESIAN_POINT('',(-241.,162.,19.7083333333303));
#667=CARTESIAN_POINT('',(-241.,162.,20.6041666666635));
#668=CARTESIAN_POINT('',(-241.,162.,22.3958333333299));
#669=CARTESIAN_POINT('',(-241.,162.,23.2916666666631));
#670=CARTESIAN_POINT('',(-241.,162.,25.0833333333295));
#671=CARTESIAN_POINT('',(-241.,162.,25.9791666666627));
#672=CARTESIAN_POINT('',(-241.,162.,27.7708333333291));
#673=CARTESIAN_POINT('',(-241.,162.,28.6666666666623));
#674=CARTESIAN_POINT('',(-241.,162.,30.4583333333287));
#675=CARTESIAN_POINT('',(-241.,162.,31.3541666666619));
#676=CARTESIAN_POINT('',(-241.,162.,33.1458333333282));
#677=CARTESIAN_POINT('',(-241.,162.,34.0416666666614));
#678=CARTESIAN_POINT('',(-241.,162.,35.8333333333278));
#679=CARTESIAN_POINT('',(-241.,162.,36.729166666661));
#680=CARTESIAN_POINT('',(-241.,162.,38.5208333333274));
#681=CARTESIAN_POINT('',(-241.,162.,39.4166666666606));
#682=CARTESIAN_POINT('',(-241.,162.,41.208333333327));
#683=CARTESIAN_POINT('',(-241.,162.,42.1041666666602));
#684=CARTESIAN_POINT('',(-241.,162.,43.8958333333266));
#685=CARTESIAN_POINT('',(-241.,162.,44.7916666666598));
#686=CARTESIAN_POINT('',(-241.,162.,46.5833333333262));
#687=CARTESIAN_POINT('',(-241.,162.,47.4791666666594));
#688=CARTESIAN_POINT('',(-241.,162.,49.2708333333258));
#689=CARTESIAN_POINT('',(-241.,162.,50.166666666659));
#690=CARTESIAN_POINT('',(-241.,162.,51.9583333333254));
#691=CARTESIAN_POINT('',(-241.,162.,52.8541666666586));
#692=CARTESIAN_POINT('',(-241.,162.,54.6458333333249));
#693=CARTESIAN_POINT('',(-241.,162.,55.5416666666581));
#694=CARTESIAN_POINT('',(-241.,162.,57.3333333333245));
#695=CARTESIAN_POINT('',(-241.,162.,58.2291666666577));
#696=CARTESIAN_POINT('',(-241.,162.,60.0208333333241));
#697=CARTESIAN_POINT('',(-241.,162.,60.9166666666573));
#698=CARTESIAN_POINT('',(-241.,162.,62.7083333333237));
#699=CARTESIAN_POINT('',(-241.,162.,63.6041666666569));
#700=CARTESIAN_POINT('',(-241.,162.,65.3958333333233));
#701=CARTESIAN_POINT('',(-241.,162.,66.2916666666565));
#702=CARTESIAN_POINT('',(-241.,162.,68.0833333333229));
#703=CARTESIAN_POINT('',(-241.,162.,68.9791666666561));
#704=CARTESIAN_POINT('',(-241.,162.,70.7708333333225));
#705=CARTESIAN_POINT('',(-241.,162.,71.6666666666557));
#706=CARTESIAN_POINT('',(-241.,162.,73.458333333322));
#707=CARTESIAN_POINT('',(-241.,162.,74.3541666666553));
#708=CARTESIAN_POINT('',(-241.,162.,76.1458333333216));
#709=CARTESIAN_POINT('',(-241.,162.,77.0416666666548));
#710=CARTESIAN_POINT('',(-241.,162.,78.8333333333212));
#711=CARTESIAN_POINT('',(-241.,162.,79.7291666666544));
#712=CARTESIAN_POINT('',(-241.,162.,81.5208333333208));
#713=CARTESIAN_POINT('',(-241.,162.,82.416666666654));
#714=CARTESIAN_POINT('',(-241.,162.,84.2083333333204));
#715=CARTESIAN_POINT('',(-241.,162.,85.1041666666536));
#716=CARTESIAN_POINT('',(-241.,162.,85.9999999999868));
#717=B_SPLINE_CURVE_WITH_KNOTS('',3,(#651,#652,#653,#654,#655,#656,#657,#658,#659,#660,#661,
#662,#663,#664,#665,#666,#667,#668,#669,#670,#671,#672,#673,#674,#675,#676,#677,#678,#679,#680,
#681,#682,#683,#684,#685,#686,#687,#688,#689,#690,#691,#692,#693,#694,#695,#696,#697,#698,#699,
#700,#701,#702,#703,#704,#705,#706,#707,#708,#709,#710,#711,#712,#713,#714,#715,#716),
.UNSPECIFIED.,.F.,.F.,(4,2,2,2,2,2,2,2,2,2,2,2,2,2,2,2,2,2,2,2,2,2,2,2,2,2,2,2,2,2,2,2,4),(0.,
2.68749999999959,5.37499999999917,8.06249999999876,10.7499999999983,13.4374999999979,
16.1249999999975,18.8124999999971,21.4999999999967,24.1874999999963,26.8749999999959,
29.5624999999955,32.249999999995,34.9374999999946,37.6249999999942,40.3124999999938,
42.9999999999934,45.687499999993,48.3749999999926,51.0624999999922,53.7499999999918,
56.4374999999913,59.1249999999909,61.8124999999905,64.4999999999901,67.1874999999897,
69.8749999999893,72.5624999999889,75.2499999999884,77.937499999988,80.6249999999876,
83.3124999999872,85.9999999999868),.UNSPECIFIED.);
#718=EDGE_CURVE('BSEAM1153',#520,#415,#717,.T.);
#719=ORIENTED_EDGE('',*,*,#521,.F.);
#720=ORIENTED_EDGE('',*,*,#416,.T.);
#721=ORIENTED_EDGE('',*,*,#718,.T.);
#722=ORIENTED_EDGE('',*,*,#718,.F.);
#723=EDGE_LOOP('',(#719,#721,#720,#722));
#724=FACE_BOUND('',#723,.T.);
#725=ADVANCED_FACE('F1153',(#724),#650,.F.);
#726=CARTESIAN_POINT('',(262.,162.,0.));
#727=DIRECTION('',(0.,0.,1.));
#728=DIRECTION('',(1.,0.,0.));
#729=AXIS2_PLACEMENT_3D('',#726,#727,#728);
#730=CYLINDRICAL_SURFACE('',#729,21.);
#731=ORIENTED_EDGE('',*,*,#510,.F.);
#732=EDGE_LOOP('',(#731));
#733=FACE_BOUND('',#732,.T.);
#734=ORIENTED_EDGE('',*,*,#405,.T.);
#735=EDGE_LOOP('',(#734));
#736=FACE_BOUND('',#735,.T.);
#737=ADVANCED_FACE('F1003',(#733,#736),#730,.F.);
#738=CARTESIAN_POINT('',(-225.,55.,46.));
#739=DIRECTION('',(0.,0.,1.));
#740=DIRECTION('',(1.,0.,0.));
#741=AXIS2_PLACEMENT_3D('',#738,#739,#740);
#742=CYLINDRICAL_SURFACE('',#741,20.);
#743=ORIENTED_EDGE('',*,*,#337,.T.);
#744=DIRECTION('',(0.,0.,1.));
#745=VECTOR('',#744,1.);
#746=CARTESIAN_POINT('',(-245.,55.,46.));
#747=LINE('',#746,#745);
#748=CARTESIAN_POINT('',(-245.,55.,46.));
#749=VERTEX_POINT('',#748);
#750=EDGE_CURVE('E319',#749,#336,#747,.T.);
#751=ORIENTED_EDGE('',*,*,#750,.F.);
#752=CARTESIAN_POINT('',(-225.,55.,46.));
#753=DIRECTION('',(0.,0.,1.));
#754=DIRECTION('',(-1.,0.,0.));
#755=AXIS2_PLACEMENT_3D('',#752,#753,#754);
#756=CIRCLE('',#755,20.);
#757=CARTESIAN_POINT('',(-225.,75.,46.));
#758=VERTEX_POINT('',#757);
#759=EDGE_CURVE('E343',#758,#749,#756,.T.);
#760=ORIENTED_EDGE('',*,*,#759,.F.);
#761=DIRECTION('',(0.,0.,1.));
#762=VECTOR('',#761,1.);
#763=CARTESIAN_POINT('',(-225.,75.,46.));
#764=LINE('',#763,#762);
#765=EDGE_CURVE('E686',#758,#334,#764,.T.);
#766=ORIENTED_EDGE('',*,*,#765,.T.);
#767=EDGE_LOOP('',(#743,#751,#760,#766));
#768=FACE_BOUND('',#767,.T.);
#769=ADVANCED_FACE('F693',(#768),#742,.F.);
#770=CARTESIAN_POINT('',(-225.,75.,46.));
#771=DIRECTION('',(0.,1.,0.));
#772=DIRECTION('',(0.,0.,1.));
#773=AXIS2_PLACEMENT_3D('',#770,#771,#772);
#774=PLANE('',#773);
#775=ORIENTED_EDGE('',*,*,#345,.T.);
#776=ORIENTED_EDGE('',*,*,#765,.F.);
#777=DIRECTION('',(-1.,0.,0.));
#778=VECTOR('',#777,1.);
#779=CARTESIAN_POINT('',(-225.,75.,46.));
#780=LINE('',#779,#778);
#781=CARTESIAN_POINT('',(225.,75.,46.));
#782=VERTEX_POINT('',#781);
#783=EDGE_CURVE('E325',#782,#758,#780,.T.);
#784=ORIENTED_EDGE('',*,*,#783,.F.);
#785=DIRECTION('',(0.,0.,1.));
#786=VECTOR('',#785,1.);
#787=CARTESIAN_POINT('',(225.,75.,46.));
#788=LINE('',#787,#786);
#789=EDGE_CURVE('E684',#782,#344,#788,.T.);
#790=ORIENTED_EDGE('',*,*,#789,.T.);
#791=EDGE_LOOP('',(#775,#776,#784,#790));
#792=FACE_BOUND('',#791,.T.);
#793=ADVANCED_FACE('F683',(#792),#774,.F.);
#794=CARTESIAN_POINT('',(225.,55.,46.));
#795=DIRECTION('',(0.,0.,1.));
#796=DIRECTION('',(1.,0.,0.));
#797=AXIS2_PLACEMENT_3D('',#794,#795,#796);
#798=CYLINDRICAL_SURFACE('',#797,20.);
#799=ORIENTED_EDGE('',*,*,#354,.T.);
#800=ORIENTED_EDGE('',*,*,#789,.F.);
#801=CARTESIAN_POINT('',(225.,55.,46.));
#802=DIRECTION('',(0.,0.,1.));
#803=DIRECTION('',(-1.,0.,0.));
#804=AXIS2_PLACEMENT_3D('',#801,#802,#803);
#805=CIRCLE('',#804,20.);
#806=CARTESIAN_POINT('',(245.,55.,46.));
#807=VERTEX_POINT('',#806);
#808=EDGE_CURVE('E665',#807,#782,#805,.T.);
#809=ORIENTED_EDGE('',*,*,#808,.F.);
#810=DIRECTION('',(0.,0.,1.));
#811=VECTOR('',#810,1.);
#812=CARTESIAN_POINT('',(245.,55.,46.));
#813=LINE('',#812,#811);
#814=EDGE_CURVE('E702',#807,#353,#813,.T.);
#815=ORIENTED_EDGE('',*,*,#814,.T.);
#816=EDGE_LOOP('',(#799,#800,#809,#815));
#817=FACE_BOUND('',#816,.T.);
#818=ADVANCED_FACE('F731',(#817),#798,.F.);
#819=CARTESIAN_POINT('',(245.,-55.,46.));
#820=DIRECTION('',(1.,0.,0.));
#821=DIRECTION('',(0.,0.,-1.));
#822=AXIS2_PLACEMENT_3D('',#819,#820,#821);
#823=PLANE('',#822);
#824=ORIENTED_EDGE('',*,*,#362,.T.);
#825=ORIENTED_EDGE('',*,*,#814,.F.);
#826=DIRECTION('',(0.,1.,0.));
#827=VECTOR('',#826,1.);
#828=CARTESIAN_POINT('',(245.,-55.,46.));
#829=LINE('',#828,#827);
#830=CARTESIAN_POINT('',(245.,-55.,46.));
#831=VERTEX_POINT('',#830);
#832=EDGE_CURVE('E662',#831,#807,#829,.T.);
#833=ORIENTED_EDGE('',*,*,#832,.F.);
#834=DIRECTION('',(0.,0.,1.));
#835=VECTOR('',#834,1.);
#836=CARTESIAN_POINT('',(245.,-55.,46.));
#837=LINE('',#836,#835);
#838=EDGE_CURVE('E704',#831,#361,#837,.T.);
#839=ORIENTED_EDGE('',*,*,#838,.T.);
#840=EDGE_LOOP('',(#824,#825,#833,#839));
#841=FACE_BOUND('',#840,.T.);
#842=ADVANCED_FACE('F730',(#841),#823,.F.);
#843=CARTESIAN_POINT('',(225.,-55.,46.));
#844=DIRECTION('',(0.,0.,1.));
#845=DIRECTION('',(1.,0.,0.));
#846=AXIS2_PLACEMENT_3D('',#843,#844,#845);
#847=CYLINDRICAL_SURFACE('',#846,20.);
#848=ORIENTED_EDGE('',*,*,#371,.T.);
#849=ORIENTED_EDGE('',*,*,#838,.F.);
#850=CARTESIAN_POINT('',(225.,-55.,46.));
#851=DIRECTION('',(0.,0.,1.));
#852=DIRECTION('',(1.,0.,0.));
#853=AXIS2_PLACEMENT_3D('',#850,#851,#852);
#854=CIRCLE('',#853,20.);
#855=CARTESIAN_POINT('',(225.,-75.,46.));
#856=VERTEX_POINT('',#855);
#857=EDGE_CURVE('E653',#856,#831,#854,.T.);
#858=ORIENTED_EDGE('',*,*,#857,.F.);
#859=DIRECTION('',(0.,0.,1.));
#860=VECTOR('',#859,1.);
#861=CARTESIAN_POINT('',(225.,-75.,46.));
#862=LINE('',#861,#860);
#863=EDGE_CURVE('E705',#856,#370,#862,.T.);
#864=ORIENTED_EDGE('',*,*,#863,.T.);
#865=EDGE_LOOP('',(#848,#849,#858,#864));
#866=FACE_BOUND('',#865,.T.);
#867=ADVANCED_FACE('F738',(#866),#847,.F.);
#868=CARTESIAN_POINT('',(-225.,-75.,46.));
#869=DIRECTION('',(0.,-1.,0.));
#870=DIRECTION('',(0.,0.,-1.));
#871=AXIS2_PLACEMENT_3D('',#868,#869,#870);
#872=PLANE('',#871);
#873=ORIENTED_EDGE('',*,*,#379,.T.);
#874=ORIENTED_EDGE('',*,*,#863,.F.);
#875=DIRECTION('',(1.,0.,0.));
#876=VECTOR('',#875,1.);
#877=CARTESIAN_POINT('',(-225.,-75.,46.));
#878=LINE('',#877,#876);
#879=CARTESIAN_POINT('',(-225.,-75.,46.));
#880=VERTEX_POINT('',#879);
#881=EDGE_CURVE('E650',#880,#856,#878,.T.);
#882=ORIENTED_EDGE('',*,*,#881,.F.);
#883=DIRECTION('',(0.,0.,1.));
#884=VECTOR('',#883,1.);
#885=CARTESIAN_POINT('',(-225.,-75.,46.));
#886=LINE('',#885,#884);
#887=EDGE_CURVE('E318',#880,#378,#886,.T.);
#888=ORIENTED_EDGE('',*,*,#887,.T.);
#889=EDGE_LOOP('',(#873,#874,#882,#888));
#890=FACE_BOUND('',#889,.T.);
#891=ADVANCED_FACE('F713',(#890),#872,.F.);
#892=CARTESIAN_POINT('',(-225.,-55.,46.));
#893=DIRECTION('',(0.,0.,1.));
#894=DIRECTION('',(1.,0.,0.));
#895=AXIS2_PLACEMENT_3D('',#892,#893,#894);
#896=CYLINDRICAL_SURFACE('',#895,20.);
#897=ORIENTED_EDGE('',*,*,#388,.T.);
#898=ORIENTED_EDGE('',*,*,#887,.F.);
#899=CARTESIAN_POINT('',(-225.,-55.,46.));
#900=DIRECTION('',(0.,0.,1.));
#901=DIRECTION('',(-1.,0.,0.));
#902=AXIS2_PLACEMENT_3D('',#899,#900,#901);
#903=CIRCLE('',#902,20.);
#904=CARTESIAN_POINT('',(-245.,-55.,46.));
#905=VERTEX_POINT('',#904);
#906=EDGE_CURVE('E638',#905,#880,#903,.T.);
#907=ORIENTED_EDGE('',*,*,#906,.F.);
#908=DIRECTION('',(0.,0.,1.));
#909=VECTOR('',#908,1.);
#910=CARTESIAN_POINT('',(-245.,-55.,46.));
#911=LINE('',#910,#909);
#912=EDGE_CURVE('E315',#905,#387,#911,.T.);
#913=ORIENTED_EDGE('',*,*,#912,.T.);
#914=EDGE_LOOP('',(#897,#898,#907,#913));
#915=FACE_BOUND('',#914,.T.);
#916=ADVANCED_FACE('F721',(#915),#896,.F.);
#917=CARTESIAN_POINT('',(-245.,-55.,46.));
#918=DIRECTION('',(-1.,0.,0.));
#919=DIRECTION('',(0.,0.,1.));
#920=AXIS2_PLACEMENT_3D('',#917,#918,#919);
#921=PLANE('',#920);
#922=ORIENTED_EDGE('',*,*,#394,.T.);
#923=ORIENTED_EDGE('',*,*,#912,.F.);
#924=DIRECTION('',(0.,-1.,0.));
#925=VECTOR('',#924,1.);
#926=CARTESIAN_POINT('',(-245.,-55.,46.));
#927=LINE('',#926,#925);
#928=EDGE_CURVE('E635',#749,#905,#927,.T.);
#929=ORIENTED_EDGE('',*,*,#928,.F.);
#930=ORIENTED_EDGE('',*,*,#750,.T.);
#931=EDGE_LOOP('',(#922,#923,#929,#930));
#932=FACE_BOUND('',#931,.T.);
#933=ADVANCED_FACE('F835',(#932),#921,.F.);
#934=CARTESIAN_POINT('',(-225.,55.,46.));
#935=DIRECTION('',(0.,0.,-1.));
#936=DIRECTION('',(-1.,0.,0.));
#937=AXIS2_PLACEMENT_3D('',#934,#935,#936);
#938=PLANE('',#937);
#939=CARTESIAN_POINT('',(0.,0.,46.));
#940=DIRECTION('',(0.,0.,1.));
#941=DIRECTION('',(1.,0.,0.));
#942=AXIS2_PLACEMENT_3D('',#939,#940,#941);
#943=CIRCLE('',#942,8.75);
#944=CARTESIAN_POINT('',(8.75,0.,46.));
#945=VERTEX_POINT('',#944);
#946=EDGE_CURVE('E820',#945,#945,#943,.T.);
#947=ORIENTED_EDGE('',*,*,#946,.F.);
#948=EDGE_LOOP('',(#947));
#949=FACE_BOUND('',#948,.T.);
#950=CARTESIAN_POINT('',(-50.,0.,46.));
#951=DIRECTION('',(0.,0.,1.));
#952=DIRECTION('',(1.,0.,0.));
#953=AXIS2_PLACEMENT_3D('',#950,#951,#952);
#954=CIRCLE('',#953,8.74999999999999);
#955=CARTESIAN_POINT('',(-41.25,0.,46.));
#956=VERTEX_POINT('',#955);
#957=EDGE_CURVE('E808',#956,#956,#954,.T.);
#958=ORIENTED_EDGE('',*,*,#957,.F.);
#959=EDGE_LOOP('',(#958));
#960=FACE_BOUND('',#959,.T.);
#961=CARTESIAN_POINT('',(-100.,0.,46.));
#962=DIRECTION('',(0.,0.,1.));
#963=DIRECTION('',(1.,0.,0.));
#964=AXIS2_PLACEMENT_3D('',#961,#962,#963);
#965=CIRCLE('',#964,8.74999999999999);
#966=CARTESIAN_POINT('',(-91.25,0.,46.));
#967=VERTEX_POINT('',#966);
#968=EDGE_CURVE('E794',#967,#967,#965,.T.);
#969=ORIENTED_EDGE('',*,*,#968,.F.);
#970=EDGE_LOOP('',(#969));
#971=FACE_BOUND('',#970,.T.);
#972=CARTESIAN_POINT('',(50.,0.,46.));
#973=DIRECTION('',(0.,0.,1.));
#974=DIRECTION('',(1.,0.,0.));
#975=AXIS2_PLACEMENT_3D('',#972,#973,#974);
#976=CIRCLE('',#975,8.74999999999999);
#977=CARTESIAN_POINT('',(58.75,0.,46.));
#978=VERTEX_POINT('',#977);
#979=EDGE_CURVE('E579',#978,#978,#976,.T.);
#980=ORIENTED_EDGE('',*,*,#979,.F.);
#981=EDGE_LOOP('',(#980));
#982=FACE_BOUND('',#981,.T.);
#983=CARTESIAN_POINT('',(100.,0.,46.));
#984=DIRECTION('',(0.,0.,1.));
#985=DIRECTION('',(1.,0.,0.));
#986=AXIS2_PLACEMENT_3D('',#983,#984,#985);
#987=CIRCLE('',#986,8.74999999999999);
#988=CARTESIAN_POINT('',(108.75,0.,46.));
#989=VERTEX_POINT('',#988);
#990=EDGE_CURVE('E571',#989,#989,#987,.T.);
#991=ORIENTED_EDGE('',*,*,#990,.F.);
#992=EDGE_LOOP('',(#991));
#993=FACE_BOUND('',#992,.T.);
#994=ORIENTED_EDGE('',*,*,#759,.T.);
#995=ORIENTED_EDGE('',*,*,#928,.T.);
#996=ORIENTED_EDGE('',*,*,#906,.T.);
#997=ORIENTED_EDGE('',*,*,#881,.T.);
#998=ORIENTED_EDGE('',*,*,#857,.T.);
#999=ORIENTED_EDGE('',*,*,#832,.T.);
#1000=ORIENTED_EDGE('',*,*,#808,.T.);
#1001=ORIENTED_EDGE('',*,*,#783,.T.);
#1002=EDGE_LOOP('',(#994,#995,#996,#997,#998,#999,#1000,#1001));
#1003=FACE_BOUND('',#1002,.T.);
#1004=ADVANCED_FACE('F677',(#949,#960,#971,#982,#993,#1003),#938,.F.);
#1005=CARTESIAN_POINT('',(-137.361609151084,197.85,56.));
#1006=DIRECTION('',(-1.,0.,0.));
#1007=DIRECTION('',(0.,0.,1.));
#1008=AXIS2_PLACEMENT_3D('',#1005,#1006,#1007);
#1009=PLANE('',#1008);
#1010=ORIENTED_EDGE('',*,*,#289,.T.);
#1011=DIRECTION('',(0.,0.,1.));
#1012=VECTOR('',#1011,1.);
#1013=CARTESIAN_POINT('',(-137.361609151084,157.85,56.));
#1014=LINE('',#1013,#1012);
#1015=CARTESIAN_POINT('',(-137.361609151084,157.85,56.));
#1016=VERTEX_POINT('',#1015);
#1017=EDGE_CURVE('E335',#1016,#282,#1014,.T.);
#1018=ORIENTED_EDGE('',*,*,#1017,.F.);
#1019=DIRECTION('',(0.,-1.,0.));
#1020=VECTOR('',#1019,1.);
#1021=CARTESIAN_POINT('',(-137.361609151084,197.85,56.));
#1022=LINE('',#1021,#1020);
#1023=EDGE_CURVE('E484',#195,#1016,#1022,.T.);
#1024=ORIENTED_EDGE('',*,*,#1023,.F.);
#1025=ORIENTED_EDGE('',*,*,#198,.T.);
#1026=EDGE_LOOP('',(#1010,#1018,#1024,#1025));
#1027=FACE_BOUND('',#1026,.T.);
#1028=ADVANCED_FACE('F834',(#1027),#1009,.F.);
#1029=CARTESIAN_POINT('',(112.638390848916,197.85,56.));
#1030=DIRECTION('',(1.,0.,0.));
#1031=DIRECTION('',(0.,0.,-1.));
#1032=AXIS2_PLACEMENT_3D('',#1029,#1030,#1031);
#1033=PLANE('',#1032);
#1034=ORIENTED_EDGE('',*,*,#257,.T.);
#1035=ORIENTED_EDGE('',*,*,#214,.F.);
#1036=DIRECTION('',(0.,1.,0.));
#1037=VECTOR('',#1036,1.);
#1038=CARTESIAN_POINT('',(112.638390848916,197.85,56.));
#1039=LINE('',#1038,#1037);
#1040=CARTESIAN_POINT('',(112.638390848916,157.85,56.));
#1041=VERTEX_POINT('',#1040);
#1042=EDGE_CURVE('E507',#1041,#205,#1039,.T.);
#1043=ORIENTED_EDGE('',*,*,#1042,.F.);
#1044=DIRECTION('',(0.,0.,1.));
#1045=VECTOR('',#1044,1.);
#1046=CARTESIAN_POINT('',(112.638390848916,157.85,56.));
#1047=LINE('',#1046,#1045);
#1048=EDGE_CURVE('E360',#1041,#256,#1047,.T.);
#1049=ORIENTED_EDGE('',*,*,#1048,.T.);
#1050=EDGE_LOOP('',(#1034,#1035,#1043,#1049));
#1051=FACE_BOUND('',#1050,.T.);
#1052=ADVANCED_FACE('F903',(#1051),#1033,.F.);
#1053=CARTESIAN_POINT('',(92.6383908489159,157.85,56.));
#1054=DIRECTION('',(0.,0.,1.));
#1055=DIRECTION('',(1.,0.,0.));
#1056=AXIS2_PLACEMENT_3D('',#1053,#1054,#1055);
#1057=CYLINDRICAL_SURFACE('',#1056,20.);
#1058=ORIENTED_EDGE('',*,*,#266,.T.);
#1059=ORIENTED_EDGE('',*,*,#1048,.F.);
#1060=CARTESIAN_POINT('',(92.6383908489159,157.85,56.));
#1061=DIRECTION('',(0.,0.,1.));
#1062=DIRECTION('',(-1.,0.,0.));
#1063=AXIS2_PLACEMENT_3D('',#1060,#1061,#1062);
#1064=CIRCLE('',#1063,20.);
#1065=CARTESIAN_POINT('',(92.6383908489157,137.85,56.));
#1066=VERTEX_POINT('',#1065);
#1067=EDGE_CURVE('E500',#1066,#1041,#1064,.T.);
#1068=ORIENTED_EDGE('',*,*,#1067,.F.);
#1069=DIRECTION('',(0.,0.,1.));
#1070=VECTOR('',#1069,1.);
#1071=CARTESIAN_POINT('',(92.6383908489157,137.85,56.));
#1072=LINE('',#1071,#1070);
#1073=EDGE_CURVE('E361',#1066,#265,#1072,.T.);
#1074=ORIENTED_EDGE('',*,*,#1073,.T.);
#1075=EDGE_LOOP('',(#1058,#1059,#1068,#1074));
#1076=FACE_BOUND('',#1075,.T.);
#1077=ADVANCED_FACE('F906',(#1076),#1057,.F.);
#1078=CARTESIAN_POINT('',(92.6383908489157,137.85,56.));
#1079=DIRECTION('',(0.,-1.,0.));
#1080=DIRECTION('',(1.,0.,0.));
#1081=AXIS2_PLACEMENT_3D('',#1078,#1079,#1080);
#1082=PLANE('',#1081);
#1083=ORIENTED_EDGE('',*,*,#274,.T.);
#1084=ORIENTED_EDGE('',*,*,#1073,.F.);
#1085=DIRECTION('',(1.,0.,0.));
#1086=VECTOR('',#1085,1.);
#1087=CARTESIAN_POINT('',(92.6383908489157,137.85,56.));
#1088=LINE('',#1087,#1086);
#1089=CARTESIAN_POINT('',(-117.361609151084,137.85,56.));
#1090=VERTEX_POINT('',#1089);
#1091=EDGE_CURVE('E374',#1090,#1066,#1088,.T.);
#1092=ORIENTED_EDGE('',*,*,#1091,.F.);
#1093=DIRECTION('',(0.,0.,1.));
#1094=VECTOR('',#1093,1.);
#1095=CARTESIAN_POINT('',(-117.361609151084,137.85,56.));
#1096=LINE('',#1095,#1094);
#1097=EDGE_CURVE('E340',#1090,#273,#1096,.T.);
#1098=ORIENTED_EDGE('',*,*,#1097,.T.);
#1099=EDGE_LOOP('',(#1083,#1084,#1092,#1098));
#1100=FACE_BOUND('',#1099,.T.);
#1101=ADVANCED_FACE('F369',(#1100),#1082,.F.);
#1102=CARTESIAN_POINT('',(-117.361609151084,157.85,56.));
#1103=DIRECTION('',(0.,0.,1.));
#1104=DIRECTION('',(1.,0.,0.));
#1105=AXIS2_PLACEMENT_3D('',#1102,#1103,#1104);
#1106=CYLINDRICAL_SURFACE('',#1105,20.);
#1107=ORIENTED_EDGE('',*,*,#283,.T.);
#1108=ORIENTED_EDGE('',*,*,#1097,.F.);
#1109=CARTESIAN_POINT('',(-117.361609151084,157.85,56.));
#1110=DIRECTION('',(0.,0.,1.));
#1111=DIRECTION('',(-1.,0.,0.));
#1112=AXIS2_PLACEMENT_3D('',#1109,#1110,#1111);
#1113=CIRCLE('',#1112,20.);
#1114=EDGE_CURVE('E488',#1016,#1090,#1113,.T.);
#1115=ORIENTED_EDGE('',*,*,#1114,.F.);
#1116=ORIENTED_EDGE('',*,*,#1017,.T.);
#1117=EDGE_LOOP('',(#1107,#1108,#1115,#1116));
#1118=FACE_BOUND('',#1117,.T.);
#1119=ADVANCED_FACE('F380',(#1118),#1106,.F.);
#1120=CARTESIAN_POINT('',(-117.361609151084,157.85,56.));
#1121=DIRECTION('',(0.,0.,-1.));
#1122=DIRECTION('',(-1.,0.,0.));
#1123=AXIS2_PLACEMENT_3D('',#1120,#1121,#1122);
#1124=PLANE('',#1123);
#1125=ORIENTED_EDGE('',*,*,#1023,.T.);
#1126=ORIENTED_EDGE('',*,*,#1114,.T.);
#1127=ORIENTED_EDGE('',*,*,#1091,.T.);
#1128=ORIENTED_EDGE('',*,*,#1067,.T.);
#1129=ORIENTED_EDGE('',*,*,#1042,.T.);
#1130=ORIENTED_EDGE('',*,*,#206,.T.);
#1131=EDGE_LOOP('',(#1125,#1126,#1127,#1128,#1129,#1130));
#1132=FACE_BOUND('',#1131,.T.);
#1133=ADVANCED_FACE('F899',(#1132),#1124,.F.);
#1134=CARTESIAN_POINT('',(92.6383908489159,-157.85,56.));
#1135=DIRECTION('',(0.,0.,1.));
#1136=DIRECTION('',(1.,0.,0.));
#1137=AXIS2_PLACEMENT_3D('',#1134,#1135,#1136);
#1138=CYLINDRICAL_SURFACE('',#1137,20.);
#1139=ORIENTED_EDGE('',*,*,#324,.T.);
#1140=DIRECTION('',(0.,0.,1.));
#1141=VECTOR('',#1140,1.);
#1142=CARTESIAN_POINT('',(92.6383908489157,-137.85,56.));
#1143=LINE('',#1142,#1141);
#1144=CARTESIAN_POINT('',(92.6383908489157,-137.85,56.));
#1145=VERTEX_POINT('',#1144);
#1146=EDGE_CURVE('E489',#1145,#316,#1143,.T.);
#1147=ORIENTED_EDGE('',*,*,#1146,.F.);
#1148=CARTESIAN_POINT('',(92.6383908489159,-157.85,56.));
#1149=DIRECTION('',(0.,0.,1.));
#1150=DIRECTION('',(1.,0.,0.));
#1151=AXIS2_PLACEMENT_3D('',#1148,#1149,#1150);
#1152=CIRCLE('',#1151,20.);
#1153=CARTESIAN_POINT('',(112.638390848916,-157.85,56.));
#1154=VERTEX_POINT('',#1153);
#1155=EDGE_CURVE('E517',#1154,#1145,#1152,.T.);
#1156=ORIENTED_EDGE('',*,*,#1155,.F.);
#1157=DIRECTION('',(0.,0.,1.));
#1158=VECTOR('',#1157,1.);
#1159=CARTESIAN_POINT('',(112.638390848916,-157.85,56.));
#1160=LINE('',#1159,#1158);
#1161=EDGE_CURVE('E779',#1154,#245,#1160,.T.);
#1162=ORIENTED_EDGE('',*,*,#1161,.T.);
#1163=EDGE_LOOP('',(#1139,#1147,#1156,#1162));
#1164=FACE_BOUND('',#1163,.T.);
#1165=ADVANCED_FACE('F886',(#1164),#1138,.F.);
#1166=CARTESIAN_POINT('',(112.638390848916,-197.85,56.));
#1167=DIRECTION('',(1.,0.,0.));
#1168=DIRECTION('',(0.,0.,-1.));
#1169=AXIS2_PLACEMENT_3D('',#1166,#1167,#1168);
#1170=PLANE('',#1169);
#1171=ORIENTED_EDGE('',*,*,#246,.T.);
#1172=ORIENTED_EDGE('',*,*,#1161,.F.);
#1173=DIRECTION('',(0.,1.,0.));
#1174=VECTOR('',#1173,1.);
#1175=CARTESIAN_POINT('',(112.638390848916,-197.85,56.));
#1176=LINE('',#1175,#1174);
#1177=EDGE_CURVE('E544',#69,#1154,#1176,.T.);
#1178=ORIENTED_EDGE('',*,*,#1177,.F.);
#1179=ORIENTED_EDGE('',*,*,#72,.T.);
#1180=EDGE_LOOP('',(#1171,#1172,#1178,#1179));
#1181=FACE_BOUND('',#1180,.T.);
#1182=ADVANCED_FACE('F882',(#1181),#1170,.F.);
#1183=CARTESIAN_POINT('',(-137.361609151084,-197.85,56.));
#1184=DIRECTION('',(-1.,0.,0.));
#1185=DIRECTION('',(0.,0.,1.));
#1186=AXIS2_PLACEMENT_3D('',#1183,#1184,#1185);
#1187=PLANE('',#1186);
#1188=ORIENTED_EDGE('',*,*,#300,.T.);
#1189=ORIENTED_EDGE('',*,*,#88,.F.);
#1190=DIRECTION('',(0.,-1.,0.));
#1191=VECTOR('',#1190,1.);
#1192=CARTESIAN_POINT('',(-137.361609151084,-197.85,56.));
#1193=LINE('',#1192,#1191);
#1194=CARTESIAN_POINT('',(-137.361609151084,-157.85,56.));
#1195=VERTEX_POINT('',#1194);
#1196=EDGE_CURVE('E534',#1195,#79,#1193,.T.);
#1197=ORIENTED_EDGE('',*,*,#1196,.F.);
#1198=DIRECTION('',(0.,0.,1.));
#1199=VECTOR('',#1198,1.);
#1200=CARTESIAN_POINT('',(-137.361609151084,-157.85,56.));
#1201=LINE('',#1200,#1199);
#1202=EDGE_CURVE('E781',#1195,#299,#1201,.T.);
#1203=ORIENTED_EDGE('',*,*,#1202,.T.);
#1204=EDGE_LOOP('',(#1188,#1189,#1197,#1203));
#1205=FACE_BOUND('',#1204,.T.);
#1206=ADVANCED_FACE('F885',(#1205),#1187,.F.);
#1207=CARTESIAN_POINT('',(-117.361609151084,-157.85,56.));
#1208=DIRECTION('',(0.,0.,1.));
#1209=DIRECTION('',(1.,0.,0.));
#1210=AXIS2_PLACEMENT_3D('',#1207,#1208,#1209);
#1211=CYLINDRICAL_SURFACE('',#1210,20.);
#1212=ORIENTED_EDGE('',*,*,#309,.T.);
#1213=ORIENTED_EDGE('',*,*,#1202,.F.);
#1214=CARTESIAN_POINT('',(-117.361609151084,-157.85,56.));
#1215=DIRECTION('',(0.,0.,1.));
#1216=DIRECTION('',(1.,0.,0.));
#1217=AXIS2_PLACEMENT_3D('',#1214,#1215,#1216);
#1218=CIRCLE('',#1217,20.);
#1219=CARTESIAN_POINT('',(-117.361609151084,-137.85,56.));
#1220=VERTEX_POINT('',#1219);
#1221=EDGE_CURVE('E531',#1220,#1195,#1218,.T.);
#1222=ORIENTED_EDGE('',*,*,#1221,.F.);
#1223=DIRECTION('',(0.,0.,1.));
#1224=VECTOR('',#1223,1.);
#1225=CARTESIAN_POINT('',(-117.361609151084,-137.85,56.));
#1226=LINE('',#1225,#1224);
#1227=EDGE_CURVE('E1286',#1220,#308,#1226,.T.);
#1228=ORIENTED_EDGE('',*,*,#1227,.T.);
#1229=EDGE_LOOP('',(#1212,#1213,#1222,#1228));
#1230=FACE_BOUND('',#1229,.T.);
#1231=ADVANCED_FACE('F889',(#1230),#1211,.F.);
#1232=CARTESIAN_POINT('',(92.6383908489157,-137.85,56.));
#1233=DIRECTION('',(0.,1.,0.));
#1234=DIRECTION('',(-1.,0.,0.));
#1235=AXIS2_PLACEMENT_3D('',#1232,#1233,#1234);
#1236=PLANE('',#1235);
#1237=ORIENTED_EDGE('',*,*,#317,.T.);
#1238=ORIENTED_EDGE('',*,*,#1227,.F.);
#1239=DIRECTION('',(-1.,0.,0.));
#1240=VECTOR('',#1239,1.);
#1241=CARTESIAN_POINT('',(92.6383908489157,-137.85,56.));
#1242=LINE('',#1241,#1240);
#1243=EDGE_CURVE('E520',#1145,#1220,#1242,.T.);
#1244=ORIENTED_EDGE('',*,*,#1243,.F.);
#1245=ORIENTED_EDGE('',*,*,#1146,.T.);
#1246=EDGE_LOOP('',(#1237,#1238,#1244,#1245));
#1247=FACE_BOUND('',#1246,.T.);
#1248=ADVANCED_FACE('F880',(#1247),#1236,.F.);
#1249=CARTESIAN_POINT('',(92.6383908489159,-157.85,56.));
#1250=DIRECTION('',(0.,0.,1.));
#1251=DIRECTION('',(1.,0.,0.));
#1252=AXIS2_PLACEMENT_3D('',#1249,#1250,#1251);
#1253=PLANE('',#1252);
#1254=ORIENTED_EDGE('',*,*,#1155,.T.);
#1255=ORIENTED_EDGE('',*,*,#1243,.T.);
#1256=ORIENTED_EDGE('',*,*,#1221,.T.);
#1257=ORIENTED_EDGE('',*,*,#1196,.T.);
#1258=ORIENTED_EDGE('',*,*,#80,.T.);
#1259=ORIENTED_EDGE('',*,*,#1177,.T.);
#1260=EDGE_LOOP('',(#1254,#1255,#1256,#1257,#1258,#1259));
#1261=FACE_BOUND('',#1260,.T.);
#1262=ADVANCED_FACE('F877',(#1261),#1253,.T.);
#1263=CARTESIAN_POINT('',(287.85,-100.,43.));
#1264=DIRECTION('',(1.,0.,0.));
#1265=DIRECTION('',(0.,1.,0.));
#1266=AXIS2_PLACEMENT_3D('',#1263,#1264,#1265);
#1267=CYLINDRICAL_SURFACE('',#1266,20.);
#1268=ORIENTED_EDGE('',*,*,#140,.T.);
#1269=DIRECTION('',(1.,0.,0.));
#1270=VECTOR('',#1269,1.);
#1271=CARTESIAN_POINT('',(287.85,-100.,23.));
#1272=LINE('',#1271,#1270);
#1273=CARTESIAN_POINT('',(287.85,-100.,23.));
#1274=VERTEX_POINT('',#1273);
#1275=EDGE_CURVE('E222',#1274,#128,#1272,.T.);
#1276=ORIENTED_EDGE('',*,*,#1275,.F.);
#1277=CARTESIAN_POINT('',(287.85,-100.,43.));
#1278=DIRECTION('',(1.,0.,0.));
#1279=DIRECTION('',(0.,1.,0.));
#1280=AXIS2_PLACEMENT_3D('',#1277,#1278,#1279);
#1281=CIRCLE('',#1280,20.);
#1282=CARTESIAN_POINT('',(287.85,-100.,63.));
#1283=VERTEX_POINT('',#1282);
#1284=EDGE_CURVE('E226',#1283,#1274,#1281,.T.);
#1285=ORIENTED_EDGE('',*,*,#1284,.F.);
#1286=DIRECTION('',(1.,0.,0.));
#1287=VECTOR('',#1286,1.);
#1288=CARTESIAN_POINT('',(287.85,-100.,63.));
#1289=LINE('',#1288,#1287);
#1290=EDGE_CURVE('E409',#1283,#139,#1289,.T.);
#1291=ORIENTED_EDGE('',*,*,#1290,.T.);
#1292=EDGE_LOOP('',(#1268,#1276,#1285,#1291));
#1293=FACE_BOUND('',#1292,.T.);
#1294=ADVANCED_FACE('F224',(#1293),#1267,.F.);
#1295=CARTESIAN_POINT('',(287.85,-100.,63.));
#1296=DIRECTION('',(0.,0.,1.));
#1297=DIRECTION('',(0.,-1.,0.));
#1298=AXIS2_PLACEMENT_3D('',#1295,#1296,#1297);
#1299=PLANE('',#1298);
#1300=ORIENTED_EDGE('',*,*,#148,.T.);
#1301=ORIENTED_EDGE('',*,*,#1290,.F.);
#1302=DIRECTION('',(0.,-1.,0.));
#1303=VECTOR('',#1302,1.);
#1304=CARTESIAN_POINT('',(287.85,-100.,63.));
#1305=LINE('',#1304,#1303);
#1306=CARTESIAN_POINT('',(287.85,100.,63.));
#1307=VERTEX_POINT('',#1306);
#1308=EDGE_CURVE('E232',#1307,#1283,#1305,.T.);
#1309=ORIENTED_EDGE('',*,*,#1308,.F.);
#1310=DIRECTION('',(1.,0.,0.));
#1311=VECTOR('',#1310,1.);
#1312=CARTESIAN_POINT('',(287.85,100.,63.));
#1313=LINE('',#1312,#1311);
#1314=EDGE_CURVE('E559',#1307,#147,#1313,.T.);
#1315=ORIENTED_EDGE('',*,*,#1314,.T.);
#1316=EDGE_LOOP('',(#1300,#1301,#1309,#1315));
#1317=FACE_BOUND('',#1316,.T.);
#1318=ADVANCED_FACE('F564',(#1317),#1299,.F.);
#1319=CARTESIAN_POINT('',(287.85,100.,43.));
#1320=DIRECTION('',(1.,0.,0.));
#1321=DIRECTION('',(0.,1.,0.));
#1322=AXIS2_PLACEMENT_3D('',#1319,#1320,#1321);
#1323=CYLINDRICAL_SURFACE('',#1322,20.);
#1324=ORIENTED_EDGE('',*,*,#155,.T.);
#1325=ORIENTED_EDGE('',*,*,#1314,.F.);
#1326=CARTESIAN_POINT('',(287.85,100.,43.));
#1327=DIRECTION('',(1.,0.,0.));
#1328=DIRECTION('',(0.,1.,0.));
#1329=AXIS2_PLACEMENT_3D('',#1326,#1327,#1328);
#1330=CIRCLE('',#1329,20.);
#1331=CARTESIAN_POINT('',(287.85,100.,23.));
#1332=VERTEX_POINT('',#1331);
#1333=EDGE_CURVE('E240',#1332,#1307,#1330,.T.);
#1334=ORIENTED_EDGE('',*,*,#1333,.F.);
#1335=DIRECTION('',(1.,0.,0.));
#1336=VECTOR('',#1335,1.);
#1337=CARTESIAN_POINT('',(287.85,100.,23.));
#1338=LINE('',#1337,#1336);
#1339=EDGE_CURVE('E231',#1332,#130,#1338,.T.);
#1340=ORIENTED_EDGE('',*,*,#1339,.T.);
#1341=EDGE_LOOP('',(#1324,#1325,#1334,#1340));
#1342=FACE_BOUND('',#1341,.T.);
#1343=ADVANCED_FACE('F869',(#1342),#1323,.F.);
#1344=CARTESIAN_POINT('',(287.85,-100.,23.));
#1345=DIRECTION('',(0.,0.,-1.));
#1346=DIRECTION('',(0.,1.,0.));
#1347=AXIS2_PLACEMENT_3D('',#1344,#1345,#1346);
#1348=PLANE('',#1347);
#1349=ORIENTED_EDGE('',*,*,#131,.T.);
#1350=ORIENTED_EDGE('',*,*,#1339,.F.);
#1351=DIRECTION('',(0.,1.,0.));
#1352=VECTOR('',#1351,1.);
#1353=CARTESIAN_POINT('',(287.85,-100.,23.));
#1354=LINE('',#1353,#1352);
#1355=EDGE_CURVE('E235',#1274,#1332,#1354,.T.);
#1356=ORIENTED_EDGE('',*,*,#1355,.F.);
#1357=ORIENTED_EDGE('',*,*,#1275,.T.);
#1358=EDGE_LOOP('',(#1349,#1350,#1356,#1357));
#1359=FACE_BOUND('',#1358,.T.);
#1360=ADVANCED_FACE('F236',(#1359),#1348,.F.);
#1361=CARTESIAN_POINT('',(287.85,-100.,43.));
#1362=DIRECTION('',(1.,0.,0.));
#1363=DIRECTION('',(0.,1.,0.));
#1364=AXIS2_PLACEMENT_3D('',#1361,#1362,#1363);
#1365=PLANE('',#1364);
#1366=ORIENTED_EDGE('',*,*,#1284,.T.);
#1367=ORIENTED_EDGE('',*,*,#1355,.T.);
#1368=ORIENTED_EDGE('',*,*,#1333,.T.);
#1369=ORIENTED_EDGE('',*,*,#1308,.T.);
#1370=EDGE_LOOP('',(#1366,#1367,#1368,#1369));
#1371=FACE_BOUND('',#1370,.T.);
#1372=ADVANCED_FACE('F242',(#1371),#1365,.T.);
#1373=CARTESIAN_POINT('',(100.,0.,46.));
#1374=DIRECTION('',(0.,0.,1.));
#1375=DIRECTION('',(1.,0.,0.));
#1376=AXIS2_PLACEMENT_3D('',#1373,#1374,#1375);
#1377=CYLINDRICAL_SURFACE('',#1376,8.74999999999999);
#1378=ORIENTED_EDGE('',*,*,#499,.F.);
#1379=EDGE_LOOP('',(#1378));
#1380=FACE_BOUND('',#1379,.T.);
#1381=ORIENTED_EDGE('',*,*,#990,.T.);
#1382=EDGE_LOOP('',(#1381));
#1383=FACE_BOUND('',#1382,.T.);
#1384=ADVANCED_FACE('F850',(#1380,#1383),#1377,.F.);
#1385=CARTESIAN_POINT('',(50.,0.,46.));
#1386=DIRECTION('',(0.,0.,1.));
#1387=DIRECTION('',(1.,0.,0.));
#1388=AXIS2_PLACEMENT_3D('',#1385,#1386,#1387);
#1389=CYLINDRICAL_SURFACE('',#1388,8.74999999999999);
#1390=ORIENTED_EDGE('',*,*,#488,.F.);
#1391=EDGE_LOOP('',(#1390));
#1392=FACE_BOUND('',#1391,.T.);
#1393=ORIENTED_EDGE('',*,*,#979,.T.);
#1394=EDGE_LOOP('',(#1393));
#1395=FACE_BOUND('',#1394,.T.);
#1396=ADVANCED_FACE('F847',(#1392,#1395),#1389,.F.);
#1397=CARTESIAN_POINT('',(-100.,0.,46.));
#1398=DIRECTION('',(0.,0.,1.));
#1399=DIRECTION('',(1.,0.,0.));
#1400=AXIS2_PLACEMENT_3D('',#1397,#1398,#1399);
#1401=CYLINDRICAL_SURFACE('',#1400,8.74999999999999);
#1402=ORIENTED_EDGE('',*,*,#477,.F.);
#1403=EDGE_LOOP('',(#1402));
#1404=FACE_BOUND('',#1403,.T.);
#1405=ORIENTED_EDGE('',*,*,#968,.T.);
#1406=EDGE_LOOP('',(#1405));
#1407=FACE_BOUND('',#1406,.T.);
#1408=ADVANCED_FACE('F849',(#1404,#1407),#1401,.F.);
#1409=CARTESIAN_POINT('',(-50.,0.,46.));
#1410=DIRECTION('',(0.,0.,1.));
#1411=DIRECTION('',(1.,0.,0.));
#1412=AXIS2_PLACEMENT_3D('',#1409,#1410,#1411);
#1413=CYLINDRICAL_SURFACE('',#1412,8.74999999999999);
#1414=ORIENTED_EDGE('',*,*,#466,.F.);
#1415=EDGE_LOOP('',(#1414));
#1416=FACE_BOUND('',#1415,.T.);
#1417=ORIENTED_EDGE('',*,*,#957,.T.);
#1418=EDGE_LOOP('',(#1417));
#1419=FACE_BOUND('',#1418,.T.);
#1420=ADVANCED_FACE('F857',(#1416,#1419),#1413,.F.);
#1421=CARTESIAN_POINT('',(0.,0.,46.));
#1422=DIRECTION('',(0.,0.,1.));
#1423=DIRECTION('',(1.,0.,0.));
#1424=AXIS2_PLACEMENT_3D('',#1421,#1422,#1423);
#1425=CYLINDRICAL_SURFACE('',#1424,8.74999999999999);
#1426=ORIENTED_EDGE('',*,*,#455,.F.);
#1427=EDGE_LOOP('',(#1426));
#1428=FACE_BOUND('',#1427,.T.);
#1429=ORIENTED_EDGE('',*,*,#946,.T.);
#1430=EDGE_LOOP('',(#1429));
#1431=FACE_BOUND('',#1430,.T.);
#1432=ADVANCED_FACE('F830',(#1428,#1431),#1425,.F.);
#1433=CLOSED_SHELL('',(#58,#117,#184,#234,#442,#553,#565,#645,#725,#737,#769,#793,#818,#842,
#867,#891,#916,#933,#1004,#1028,#1052,#1077,#1101,#1119,#1133,#1165,#1182,#1206,#1231,#1248,
#1262,#1294,#1318,#1343,#1360,#1372,#1384,#1396,#1408,#1420,#1432));
#1434=MANIFOLD_SOLID_BREP('B2',#1433);
#1435=ADVANCED_BREP_SHAPE_REPRESENTATION('',(#18,#1434),#14);
#1436=SHAPE_DEFINITION_REPRESENTATION(#9,#1435);
ENDSEC;
END-ISO-10303-21;
